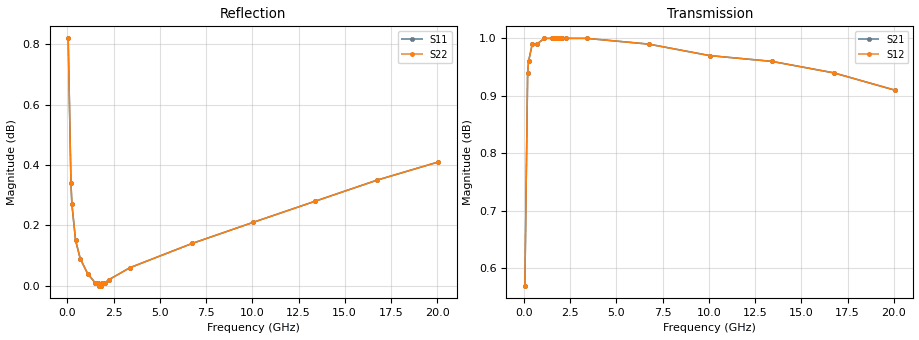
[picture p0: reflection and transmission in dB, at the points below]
! AVX Thin Film Operation		Date: may 2004
! Description: Accu-P® Series, Thin Film, SMD, RF Capacitor
! Part Number: 0201ZK220JBW
! 50 MHz  -  10.05 GHz
! Serial Measurements
# mhz S db R 50
!	S11		S21		S12		S22
!	dB	Phase	dB	Phase	dB	Phase	dB	Phase
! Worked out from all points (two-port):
!   401 points, 50 MHz to 20.05 GHz, reference 50 ohm
!   highest |S21| = 1.00 dB at 1.1 GHz (marker M1); lowest = 0.6 dB at 50 MHz (marker M2)
!   |S21| within 3 dB of the highest: start of sweep to end of sweep
!   lowest |S11| = 0.0 dB at 1.8 GHz (marker M3)
!   |S11| at or under -10 dB: nowhere
!   |S22| runs from 0.0 to 0.8 dB; largest |S21 - S12| = 0
!   S11 on the Smith chart (normalised r, x): 50 MHz: -0.52, -3.13; 450 MHz: -0.02, -1.17; 1.8 GHz: -0.00, +6.09; 20.05 GHz: -0.08, +1.55
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50  0.82 -34.7  0.57 55.3  0.57 55.3  0.82 -34.7
200  0.34 -70.1  0.94 19.6  0.94 19.6  0.34 -70.1
250  0.27 -73.9  0.96 15.8  0.96 15.8  0.27 -73.9
450  0.15 -80.9  0.99 8.6  0.99 8.6  0.15 -80.9
700  0.09 -84.0  0.99 5.0  0.99 5.0  0.09 -84.0
1100  0.04 -85.5  1.00 2.3  1.00 2.3  0.04 -85.5
1500  0.01 -83.0  1.00 0.8  1.00 0.8  0.01 -83.0
1600  0.01 -79.7  1.00 0.5  1.00 0.5  0.01 -79.7
1650  0.01 -76.3  1.00 0.4  1.00 0.4  0.01 -76.3
1700  0.00 -69.1  1.00 0.2  1.00 0.2  0.00 -69.1
1800  0.00 18.7  1.00 -0.0  1.00 -0.0  0.00 18.7
1850  0.00 60.4  1.00 -0.2  1.00 -0.2  0.00 60.4
1900  0.01 72.2  1.00 -0.3  1.00 -0.3  0.01 72.2
1950  0.01 77.1  1.00 -0.4  1.00 -0.4  0.01 77.1
2050  0.01 81.4  1.00 -0.6  1.00 -0.6  0.01 81.4
2250  0.02 84.2  1.00 -1.1  1.00 -1.1  0.02 84.2
3400  0.06 85.2  1.00 -3.2  1.00 -3.2  0.06 85.2
6750  0.14 81.3  0.99 -8.1  0.99 -8.1  0.14 81.3
10050  0.21 77.2  0.97 -12.4  0.97 -12.4  0.21 77.2
13400  0.28 73.1  0.96 -16.6  0.96 -16.6  0.28 73.1
16750  0.35 69.3  0.94 -20.5  0.94 -20.5  0.35 69.3
20050  0.41 65.6  0.91 -24.2  0.91 -24.2  0.41 65.6
